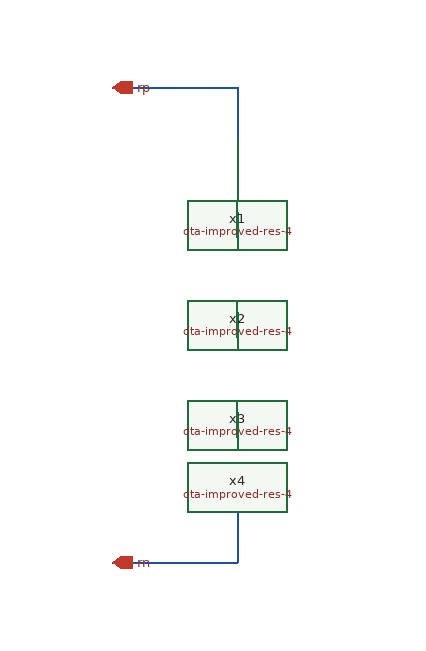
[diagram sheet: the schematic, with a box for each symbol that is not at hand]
v {xschem version=3.4.5 file_version=1.2
}
G {}
K {}
V {}
S {}
E {}
N 180 -520 280 -520 {
lab=rp}
N 280 -520 280 -480 {
lab=rp}
N 280 -420 280 -400 {
lab=#net2}
N 280 -340 280 -320 {
lab=#net3}
N 280 -260 280 -240 {
lab=#net4}
N 280 -180 280 -140 {
lab=rn}
N 180 -140 280 -140 {
lab=rn}
C {devices/title.sym} 160 -30 0 0 {name=l5 author="Copyright 2024 Harald Pretl"}
C {iopin.sym} 180 -520 0 1 {name=p2 lab=rp}
C {iopin.sym} 180 -140 0 1 {name=p1 lab=rn}
C {ota-improved-res-4.sym} 280 -420 0 0 {name=x1}
C {ota-improved-res-4.sym} 280 -340 0 0 {name=x2}
C {ota-improved-res-4.sym} 280 -260 0 0 {name=x3}
C {ota-improved-res-4.sym} 280 -180 0 0 {name=x4}
